VERSION 5.7 ;
  NOWIREEXTENSIONATPIN ON ;
  DIVIDERCHAR "/" ;
  BUSBITCHARS "[]" ;
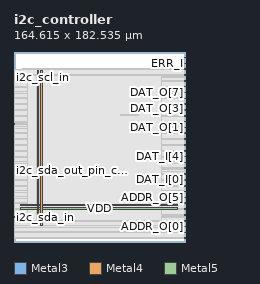
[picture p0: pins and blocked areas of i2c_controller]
MACRO i2c_controller
  CLASS BLOCK ;
  FOREIGN i2c_controller ;
  ORIGIN 0.000 0.000 ;
  SIZE 164.615 BY 182.535 ;
  PIN ACK_I
    DIRECTION INPUT ;
    USE SIGNAL ;
    ANTENNAGATEAREA 0.396000 ;
    PORT
      LAYER Metal3 ;
        RECT 164.055 165.760 164.615 166.320 ;
    END
  END ACK_I
  PIN ADDR_O[0]
    DIRECTION OUTPUT ;
    USE SIGNAL ;
    ANTENNADIFFAREA 0.897600 ;
    PORT
      LAYER Metal3 ;
        RECT 164.055 14.560 164.615 15.120 ;
    END
  END ADDR_O[0]
  PIN ADDR_O[1]
    DIRECTION OUTPUT ;
    USE SIGNAL ;
    ANTENNADIFFAREA 0.897600 ;
    PORT
      LAYER Metal3 ;
        RECT 164.055 20.160 164.615 20.720 ;
    END
  END ADDR_O[1]
  PIN ADDR_O[2]
    DIRECTION OUTPUT ;
    USE SIGNAL ;
    ANTENNADIFFAREA 0.897600 ;
    PORT
      LAYER Metal3 ;
        RECT 164.055 25.760 164.615 26.320 ;
    END
  END ADDR_O[2]
  PIN ADDR_O[3]
    DIRECTION OUTPUT ;
    USE SIGNAL ;
    ANTENNADIFFAREA 0.897600 ;
    PORT
      LAYER Metal3 ;
        RECT 164.055 31.360 164.615 31.920 ;
    END
  END ADDR_O[3]
  PIN ADDR_O[4]
    DIRECTION OUTPUT ;
    USE SIGNAL ;
    ANTENNADIFFAREA 0.897600 ;
    PORT
      LAYER Metal3 ;
        RECT 164.055 36.960 164.615 37.520 ;
    END
  END ADDR_O[4]
  PIN ADDR_O[5]
    DIRECTION OUTPUT ;
    USE SIGNAL ;
    ANTENNADIFFAREA 0.897600 ;
    PORT
      LAYER Metal3 ;
        RECT 164.055 42.560 164.615 43.120 ;
    END
  END ADDR_O[5]
  PIN ADDR_O[6]
    DIRECTION OUTPUT ;
    USE SIGNAL ;
    ANTENNADIFFAREA 0.897600 ;
    PORT
      LAYER Metal3 ;
        RECT 164.055 48.160 164.615 48.720 ;
    END
  END ADDR_O[6]
  PIN ADDR_O[7]
    DIRECTION OUTPUT ;
    USE SIGNAL ;
    ANTENNADIFFAREA 0.897600 ;
    PORT
      LAYER Metal3 ;
        RECT 164.055 53.760 164.615 54.320 ;
    END
  END ADDR_O[7]
  PIN CLK_I
    DIRECTION INPUT ;
    USE SIGNAL ;
    ANTENNAGATEAREA 4.738000 ;
    PORT
      LAYER Metal3 ;
        RECT 164.055 3.360 164.615 3.920 ;
    END
  END CLK_I
  PIN CYC_O
    DIRECTION OUTPUT ;
    USE SIGNAL ;
    ANTENNADIFFAREA 0.897600 ;
    PORT
      LAYER Metal3 ;
        RECT 164.055 148.960 164.615 149.520 ;
    END
  END CYC_O
  PIN DAT_I[0]
    DIRECTION INPUT ;
    USE SIGNAL ;
    ANTENNAGATEAREA 0.396000 ;
    PORT
      LAYER Metal3 ;
        RECT 164.055 59.360 164.615 59.920 ;
    END
  END DAT_I[0]
  PIN DAT_I[1]
    DIRECTION INPUT ;
    USE SIGNAL ;
    ANTENNAGATEAREA 0.396000 ;
    PORT
      LAYER Metal3 ;
        RECT 164.055 64.960 164.615 65.520 ;
    END
  END DAT_I[1]
  PIN DAT_I[2]
    DIRECTION INPUT ;
    USE SIGNAL ;
    ANTENNAGATEAREA 0.396000 ;
    PORT
      LAYER Metal3 ;
        RECT 164.055 70.560 164.615 71.120 ;
    END
  END DAT_I[2]
  PIN DAT_I[3]
    DIRECTION INPUT ;
    USE SIGNAL ;
    ANTENNAGATEAREA 0.396000 ;
    PORT
      LAYER Metal3 ;
        RECT 164.055 76.160 164.615 76.720 ;
    END
  END DAT_I[3]
  PIN DAT_I[4]
    DIRECTION INPUT ;
    USE SIGNAL ;
    ANTENNAGATEAREA 0.396000 ;
    PORT
      LAYER Metal3 ;
        RECT 164.055 81.760 164.615 82.320 ;
    END
  END DAT_I[4]
  PIN DAT_I[5]
    DIRECTION INPUT ;
    USE SIGNAL ;
    ANTENNAGATEAREA 0.396000 ;
    PORT
      LAYER Metal3 ;
        RECT 164.055 87.360 164.615 87.920 ;
    END
  END DAT_I[5]
  PIN DAT_I[6]
    DIRECTION INPUT ;
    USE SIGNAL ;
    ANTENNAGATEAREA 0.396000 ;
    PORT
      LAYER Metal3 ;
        RECT 164.055 92.960 164.615 93.520 ;
    END
  END DAT_I[6]
  PIN DAT_I[7]
    DIRECTION INPUT ;
    USE SIGNAL ;
    ANTENNAGATEAREA 0.396000 ;
    PORT
      LAYER Metal3 ;
        RECT 164.055 98.560 164.615 99.120 ;
    END
  END DAT_I[7]
  PIN DAT_O[0]
    DIRECTION OUTPUT ;
    USE SIGNAL ;
    ANTENNADIFFAREA 0.897600 ;
    PORT
      LAYER Metal3 ;
        RECT 164.055 104.160 164.615 104.720 ;
    END
  END DAT_O[0]
  PIN DAT_O[1]
    DIRECTION OUTPUT ;
    USE SIGNAL ;
    ANTENNADIFFAREA 0.897600 ;
    PORT
      LAYER Metal3 ;
        RECT 164.055 109.760 164.615 110.320 ;
    END
  END DAT_O[1]
  PIN DAT_O[2]
    DIRECTION OUTPUT ;
    USE SIGNAL ;
    ANTENNADIFFAREA 0.897600 ;
    PORT
      LAYER Metal3 ;
        RECT 164.055 115.360 164.615 115.920 ;
    END
  END DAT_O[2]
  PIN DAT_O[3]
    DIRECTION OUTPUT ;
    USE SIGNAL ;
    ANTENNADIFFAREA 0.897600 ;
    PORT
      LAYER Metal3 ;
        RECT 164.055 120.960 164.615 121.520 ;
    END
  END DAT_O[3]
  PIN DAT_O[4]
    DIRECTION OUTPUT ;
    USE SIGNAL ;
    ANTENNADIFFAREA 0.897600 ;
    PORT
      LAYER Metal3 ;
        RECT 164.055 126.560 164.615 127.120 ;
    END
  END DAT_O[4]
  PIN DAT_O[5]
    DIRECTION OUTPUT ;
    USE SIGNAL ;
    ANTENNADIFFAREA 0.897600 ;
    PORT
      LAYER Metal3 ;
        RECT 164.055 132.160 164.615 132.720 ;
    END
  END DAT_O[5]
  PIN DAT_O[6]
    DIRECTION OUTPUT ;
    USE SIGNAL ;
    ANTENNADIFFAREA 0.897600 ;
    PORT
      LAYER Metal3 ;
        RECT 164.055 137.760 164.615 138.320 ;
    END
  END DAT_O[6]
  PIN DAT_O[7]
    DIRECTION OUTPUT ;
    USE SIGNAL ;
    ANTENNADIFFAREA 0.897600 ;
    PORT
      LAYER Metal3 ;
        RECT 164.055 143.360 164.615 143.920 ;
    END
  END DAT_O[7]
  PIN ERR_I
    DIRECTION INPUT ;
    USE SIGNAL ;
    PORT
      LAYER Metal3 ;
        RECT 164.055 171.360 164.615 171.920 ;
    END
  END ERR_I
  PIN RST_I
    DIRECTION INPUT ;
    USE SIGNAL ;
    ANTENNAGATEAREA 0.396000 ;
    PORT
      LAYER Metal3 ;
        RECT 164.055 8.960 164.615 9.520 ;
    END
  END RST_I
  PIN RTY_I
    DIRECTION INPUT ;
    USE SIGNAL ;
    PORT
      LAYER Metal3 ;
        RECT 164.055 176.960 164.615 177.520 ;
    END
  END RTY_I
  PIN STB_O
    DIRECTION OUTPUT ;
    USE SIGNAL ;
    ANTENNADIFFAREA 0.897600 ;
    PORT
      LAYER Metal3 ;
        RECT 164.055 154.560 164.615 155.120 ;
    END
  END STB_O
  PIN VDD
    DIRECTION INOUT ;
    USE POWER ;
    PORT
      LAYER Metal4 ;
        RECT 22.240 15.380 23.840 164.940 ;
    END
    PORT
      LAYER Metal5 ;
        RECT 6.720 31.530 157.360 33.130 ;
    END
  END VDD
  PIN VSS
    DIRECTION INOUT ;
    USE GROUND ;
    PORT
      LAYER Metal4 ;
        RECT 25.540 15.380 27.140 164.940 ;
    END
    PORT
      LAYER Metal5 ;
        RECT 6.720 34.830 157.360 36.430 ;
    END
  END VSS
  PIN WE_O
    DIRECTION OUTPUT ;
    USE SIGNAL ;
    ANTENNADIFFAREA 0.897600 ;
    PORT
      LAYER Metal3 ;
        RECT 164.055 160.160 164.615 160.720 ;
    END
  END WE_O
  PIN i2c_scl_in
    DIRECTION INPUT ;
    USE SIGNAL ;
    ANTENNAGATEAREA 0.396000 ;
    PORT
      LAYER Metal3 ;
        RECT 0.000 157.920 0.560 158.480 ;
    END
  END i2c_scl_in
  PIN i2c_sda_in
    DIRECTION INPUT ;
    USE SIGNAL ;
    ANTENNAGATEAREA 0.396000 ;
    PORT
      LAYER Metal3 ;
        RECT 0.000 23.520 0.560 24.080 ;
    END
  END i2c_sda_in
  PIN i2c_sda_out_pin_ctrl
    DIRECTION OUTPUT ;
    USE SIGNAL ;
    ANTENNADIFFAREA 0.897600 ;
    PORT
      LAYER Metal3 ;
        RECT 0.000 68.320 0.560 68.880 ;
    END
  END i2c_sda_out_pin_ctrl
  PIN i2c_sda_out_pin_ctrl_n
    DIRECTION OUTPUT ;
    USE SIGNAL ;
    ANTENNADIFFAREA 0.897600 ;
    PORT
      LAYER Metal3 ;
        RECT 0.000 113.120 0.560 113.680 ;
    END
  END i2c_sda_out_pin_ctrl_n
  OBS
      LAYER Nwell ;
        RECT 6.290 15.250 157.790 165.070 ;
      LAYER Metal1 ;
        RECT 6.720 15.380 157.360 164.940 ;
      LAYER Metal2 ;
        RECT 7.980 3.450 156.100 166.230 ;
      LAYER Metal3 ;
        RECT 0.560 165.460 163.755 166.180 ;
        RECT 0.560 161.020 164.055 165.460 ;
        RECT 0.560 159.860 163.755 161.020 ;
        RECT 0.560 158.780 164.055 159.860 ;
        RECT 0.860 157.620 164.055 158.780 ;
        RECT 0.560 155.420 164.055 157.620 ;
        RECT 0.560 154.260 163.755 155.420 ;
        RECT 0.560 149.820 164.055 154.260 ;
        RECT 0.560 148.660 163.755 149.820 ;
        RECT 0.560 144.220 164.055 148.660 ;
        RECT 0.560 143.060 163.755 144.220 ;
        RECT 0.560 138.620 164.055 143.060 ;
        RECT 0.560 137.460 163.755 138.620 ;
        RECT 0.560 133.020 164.055 137.460 ;
        RECT 0.560 131.860 163.755 133.020 ;
        RECT 0.560 127.420 164.055 131.860 ;
        RECT 0.560 126.260 163.755 127.420 ;
        RECT 0.560 121.820 164.055 126.260 ;
        RECT 0.560 120.660 163.755 121.820 ;
        RECT 0.560 116.220 164.055 120.660 ;
        RECT 0.560 115.060 163.755 116.220 ;
        RECT 0.560 113.980 164.055 115.060 ;
        RECT 0.860 112.820 164.055 113.980 ;
        RECT 0.560 110.620 164.055 112.820 ;
        RECT 0.560 109.460 163.755 110.620 ;
        RECT 0.560 105.020 164.055 109.460 ;
        RECT 0.560 103.860 163.755 105.020 ;
        RECT 0.560 99.420 164.055 103.860 ;
        RECT 0.560 98.260 163.755 99.420 ;
        RECT 0.560 93.820 164.055 98.260 ;
        RECT 0.560 92.660 163.755 93.820 ;
        RECT 0.560 88.220 164.055 92.660 ;
        RECT 0.560 87.060 163.755 88.220 ;
        RECT 0.560 82.620 164.055 87.060 ;
        RECT 0.560 81.460 163.755 82.620 ;
        RECT 0.560 77.020 164.055 81.460 ;
        RECT 0.560 75.860 163.755 77.020 ;
        RECT 0.560 71.420 164.055 75.860 ;
        RECT 0.560 70.260 163.755 71.420 ;
        RECT 0.560 69.180 164.055 70.260 ;
        RECT 0.860 68.020 164.055 69.180 ;
        RECT 0.560 65.820 164.055 68.020 ;
        RECT 0.560 64.660 163.755 65.820 ;
        RECT 0.560 60.220 164.055 64.660 ;
        RECT 0.560 59.060 163.755 60.220 ;
        RECT 0.560 54.620 164.055 59.060 ;
        RECT 0.560 53.460 163.755 54.620 ;
        RECT 0.560 49.020 164.055 53.460 ;
        RECT 0.560 47.860 163.755 49.020 ;
        RECT 0.560 43.420 164.055 47.860 ;
        RECT 0.560 42.260 163.755 43.420 ;
        RECT 0.560 37.820 164.055 42.260 ;
        RECT 0.560 36.660 163.755 37.820 ;
        RECT 0.560 32.220 164.055 36.660 ;
        RECT 0.560 31.060 163.755 32.220 ;
        RECT 0.560 26.620 164.055 31.060 ;
        RECT 0.560 25.460 163.755 26.620 ;
        RECT 0.560 24.380 164.055 25.460 ;
        RECT 0.860 23.220 164.055 24.380 ;
        RECT 0.560 21.020 164.055 23.220 ;
        RECT 0.560 19.860 163.755 21.020 ;
        RECT 0.560 15.420 164.055 19.860 ;
        RECT 0.560 14.260 163.755 15.420 ;
        RECT 0.560 9.820 164.055 14.260 ;
        RECT 0.560 8.660 163.755 9.820 ;
        RECT 0.560 4.220 164.055 8.660 ;
        RECT 0.560 3.500 163.755 4.220 ;
      LAYER Metal4 ;
        RECT 13.020 20.810 21.940 159.510 ;
        RECT 24.140 20.810 25.240 159.510 ;
        RECT 27.440 20.810 142.100 159.510 ;
      LAYER Metal5 ;
        RECT 102.540 121.730 119.220 122.170 ;
  END
END i2c_controller
END LIBRARY

